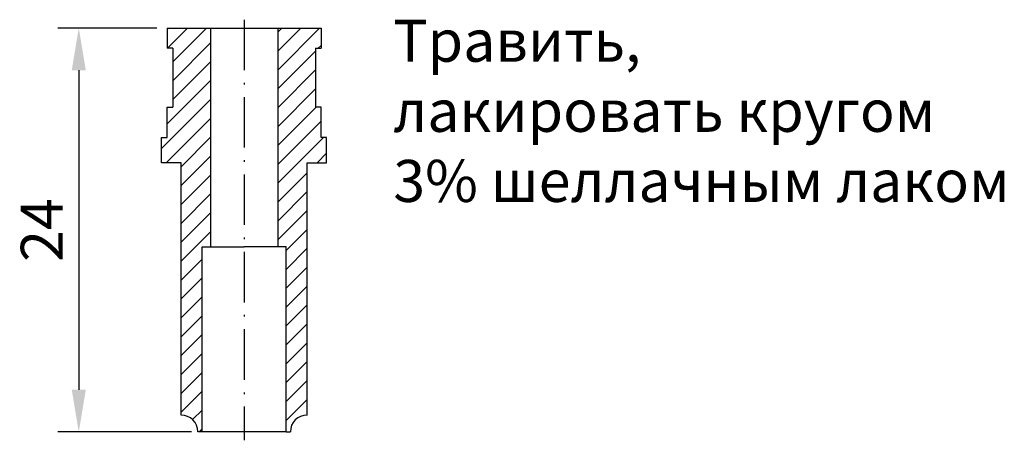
# Model space of a CAD drawing. Units: millimetres. Extents: x -13.4 to 45.2, y -24.5 to 0.5.
import ezdxf

# ---------------------------------------------------------------- set-up
doc = ezdxf.new("R2010")
doc.units = ezdxf.units.MM
doc.linetypes.add('ACAD_ISO10W100', pattern=[18, 12, -3, 0, -3])
doc.dimstyles.new('ISO-25', dxfattribs={"dimtxt": 2.5, "dimasz": 2.5, "dimexe": 1.25, "dimexo": 0.625, "dimtad": 1, "dimtxsty": 'Standard', "dimcen": 2.5, "dimadec": 0, "dimazin": 0, "dimtfac": 1, "dimtmove": 0, "dimatfit": 3, "dimfxl": 0, "dimarcsym": 0})

# ---------------------------------------------------------------- blocks, each defined once
blk = doc.blocks.new('*D5')
at = {"color": 0, "linetype": 'ByBlock', "lineweight": -2}
for p, q in [((-5.2, 0), (-11.087, 0)), ((-9.837, -2.5), (-9.837, -21.5)), ((-3.125, -24), (-11.087, -24))]:
    blk.add_line(p, q, dxfattribs=at)
at = {"color": 0, "linetype": 'ByBlock', "lineweight": 15}
for points in [[(-10.254, -2.5), (-9.42, -2.5), (-9.837, 0)], [(-10.254, -21.5), (-9.42, -21.5), (-9.837, -24)]]:
    blk.add_solid(points, dxfattribs=at)
at = {"layer": 'Defpoints', "color": 0, "linetype": 'ByBlock', "lineweight": 15}
for p in [(-4.575, 0), (-9.837, -24), (-2.5, -24)]:
    blk.add_point(p, dxfattribs=at)
at = {"color": 0, "linetype": 'ByBlock', "lineweight": 15, "insert": (-11.712, -12), "char_height": 2.5, "attachment_point": 5, "rotation": 90}
blk.add_mtext('24', dxfattribs=at)

msp = doc.modelspace()

# ---------------------------------------------------------------- hatches: boundary and pattern name
at = {"linetype": 'ByBlock', "lineweight": 15}
h = msp.add_hatch(dxfattribs=at)
h.set_pattern_fill('ANSI31', scale=0.25, angle=180, style=0)
h.paths.add_polyline_path([(3.75, -8), (4.91, -8), (4.91, -6.5), (4.575, -6.5), (4.575, -4.7), (4.25, -4.7), (4.25, -1.2), (4.575, -1.2), (4.575, 0), (2, 0), (2, -13), (2.5, -13), (2.5, -24), (2.75, -24, -0.414214), (3.75, -23)])
h.paths.add_polyline_path([(-2, 0), (-4.575, 0), (-4.575, -1.2), (-4.25, -1.2), (-4.25, -4.7), (-4.575, -4.7), (-4.575, -6.5), (-4.91, -6.5), (-4.91, -8), (-3.75, -8), (-3.75, -23, -0.414214), (-2.75, -24), (-2.5, -24), (-2.5, -13), (-2, -13)])

# ---------------------------------------------------------------- linework, layer by layer
at = {"color": 7, "linetype": 'ByBlock', "lineweight": 30}
for p, q in [((-4.575, 0), (4.575, 0)), ((-4.575, 0), (-4.575, -1.2)), ((-2, 0), (-2, -13)), ((2, 0), (2, -13)), ((4.575, 0), (4.575, -1.2)), ((-4.25, -1.2), (-4.575, -1.2)), ((-4.25, -1.2), (-4.25, -4.7)), ((4.25, -1.2), (4.575, -1.2)), ((4.25, -1.2), (4.25, -4.7)), ((-4.575, -4.7), (-4.25, -4.7)), ((-4.575, -6.5), (-4.575, -4.7)), ((4.575, -4.7), (4.25, -4.7)), ((4.575, -6.5), (4.575, -4.7)), ((-4.91, -8), (-4.91, -6.5)), ((-4.91, -6.5), (-4.575, -6.5)), ((4.91, -6.5), (4.575, -6.5)), ((4.91, -8), (4.91, -6.5)), ((-3.75, -8), (-4.91, -8)), ((-3.75, -23), (-3.75, -8)), ((3.75, -23), (3.75, -8)), ((3.75, -8), (4.91, -8)), ((-2.5, -13), (0, -13)), ((-2.5, -24), (-2.5, -13)), ((2.5, -13), (0, -13)), ((2.5, -24), (2.5, -13)), ((-2.5, -24), (-2.75, -24)), ((2.5, -24), (-2.5, -24)), ((2.5, -24), (2.75, -24))]:
    msp.add_line(p, q, dxfattribs=at)
at = {"color": 1, "linetype": 'ACAD_ISO10W100', "lineweight": 25, "ltscale": 0.25}
msp.add_line((0, 0.5), (0, -24.5), dxfattribs=at)
at = {"color": 7, "linetype": 'ByBlock', "lineweight": 30}
for centre, start, end in [((-3.75, -24), 0, 90), ((3.75, -24), 90, 180)]:
    msp.add_arc(centre, 1, start, end, dxfattribs=at)

# ---------------------------------------------------------------- texts
at = {"color": 7, "linetype": 'ByBlock', "lineweight": 15}
for s, p in [('Травить,', (8.874, -2)), ('лакировать кругом', (8.874, -6.166)), ('3% шеллачным лаком', (8.874, -10.333))]:
    msp.add_text(s, height=2.5, dxfattribs=at).set_placement(p)

# ---------------------------------------------------------------- dimensions: what is measured, and where the dimension line sits
dim = msp.add_linear_dim(base=(-9.837, -24), p1=(-4.575, 0), p2=(-2.5, -24), angle=90, dimstyle='ISO-25', dxfattribs=at)
dim.commit()
dim.dimension.update_dxf_attribs({"geometry": '*D5', "text_midpoint": (-11.712, -12)})

doc.saveas('drawing.dxf')
